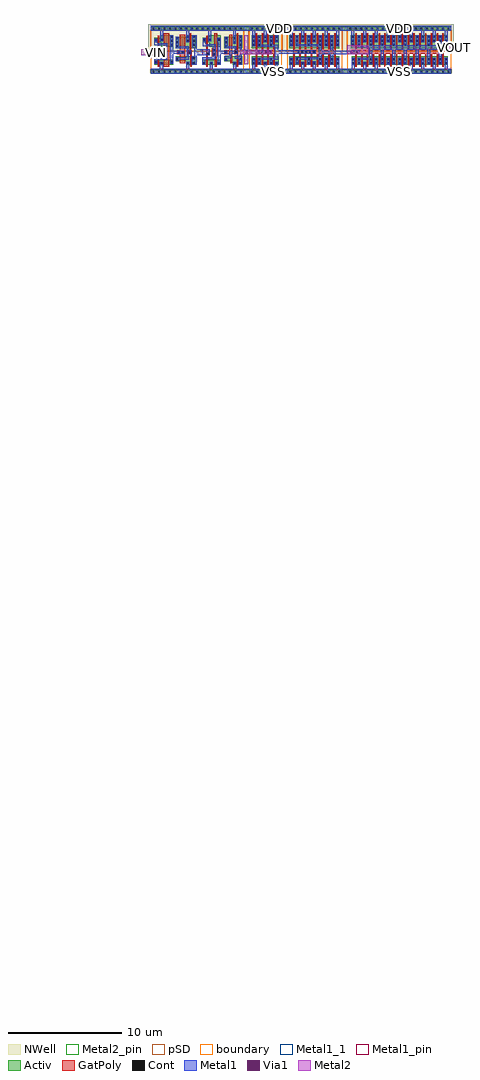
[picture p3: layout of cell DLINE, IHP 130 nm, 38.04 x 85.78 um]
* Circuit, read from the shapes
.subckt DLINE VDD VIN VOUT VSS
XM1 VSS VIN n1 VSS sg13_lv_nmos w=0.42u l=0.13u
XM2 n2 n1 VSS VSS sg13_lv_nmos w=0.42u l=0.5u
XM3 VSS n2 n3 VSS sg13_lv_nmos w=0.42u l=0.5u
XM4 sg13g2_dlygate4sd2_1_0/A n3 VSS VSS sg13_lv_nmos w=0.74u l=0.13u
XM5 VSS sg13g2_dlygate4sd2_1_0/A n4 VSS sg13_lv_nmos w=0.42u l=0.13u
XM6 n5 n4 VSS VSS sg13_lv_nmos w=0.42u l=0.18u
XM7 VSS n5 n6 VSS sg13_lv_nmos w=0.42u l=0.18u
XM8 sg13g2_dlygate4sd2_1_0/X n6 VSS VSS sg13_lv_nmos w=0.74u l=0.13u
XM9 n7 sg13g2_dlygate4sd2_1_0/X VSS VSS sg13_lv_nmos w=0.74u l=0.13u m=4
XM10 sg13g2_inv_16$1_4/A n7 VSS VSS sg13_lv_nmos w=0.74u l=0.13u m=8
XM11 VOUT sg13g2_inv_16$1_4/A VSS VSS sg13_lv_nmos w=0.74u l=0.13u m=16
XM12 VDD VIN n1 VDD sg13_lv_pmos w=0.42u l=0.13u
XM13 n2 n1 VDD VDD sg13_lv_pmos w=1u l=0.5u
XM14 VDD n2 n3 VDD sg13_lv_pmos w=1u l=0.5u
XM15 sg13g2_dlygate4sd2_1_0/A n3 VDD VDD sg13_lv_pmos w=1.12u l=0.13u
XM16 VDD sg13g2_dlygate4sd2_1_0/A n4 VDD sg13_lv_pmos w=0.42u l=0.13u
XM17 n5 n4 VDD VDD sg13_lv_pmos w=1u l=0.25u
XM18 VDD n5 n6 VDD sg13_lv_pmos w=1u l=0.25u
XM19 sg13g2_dlygate4sd2_1_0/X n6 VDD VDD sg13_lv_pmos w=1.12u l=0.13u
XM20 n7 sg13g2_dlygate4sd2_1_0/X VDD VDD sg13_lv_pmos w=1.12u l=0.13u m=4
XM21 sg13g2_inv_16$1_4/A n7 VDD VDD sg13_lv_pmos w=1.12u l=0.13u m=8
XM22 VOUT sg13g2_inv_16$1_4/A VDD VDD sg13_lv_pmos w=1.12u l=0.13u m=16
.ends

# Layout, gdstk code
from math import pi, radians
import gdstk
lib = gdstk.Library(unit=1e-6, precision=1e-09)
def R(c, l, rs):  # rectangles x0, y0, x1, y1
    for r in rs: c.add(gdstk.rectangle(r[:2], r[2:], *l))
def A(c, l, x, y, w, h, nx, ny, dx, dy):  # array of equal rectangles
    R(c, l, [(x+i*dx, y+j*dy, x+i*dx+w, y+j*dy+h) for i in range(nx) for j in range(ny)])
def P(c, l, *ps):  # polygons
    for p in ps: c.add(gdstk.Polygon(p, *l))
Activ = (1, 0)
GatPoly = (5, 0)
Cont = (6, 0)
Metal1 = (8, 0)
Metal1_1 = (8, 1)
Metal1_pin = (8, 2)
Metal2 = (10, 0)
Metal2_pin = (10, 2)
pSD = (14, 0)
Via1 = (19, 0)
NWell = (31, 0)
boundary = (189, 4)

sg13g2_dlygate4sd2_1 = lib.new_cell('sg13g2_dlygate4sd2_1')
R(sg13g2_dlygate4sd2_1, Activ, [(-4.79,81.345,-0.95,81.645), (-4.6,82.085,-2.98,82.505), (-4.79,85.125,-0.95,85.425)])
P(sg13g2_dlygate4sd2_1, Activ, [(-1.895,82.085),(-1.895,82.405),(-2.66,82.405),(-2.66,82.825),(-1.085,82.825),(-1.085,82.085)],
  [(-2.66,83.555),(-2.66,84.555),(-1.88,84.555),(-1.88,84.675),(-1.085,84.675),(-1.085,83.555)],
  [(-3.99,83.675),(-3.99,84.05),(-4.57,84.05),(-4.57,84.47),(-3.99,84.47),(-3.99,84.675),(-2.95,84.675),(-2.95,83.675)])
P(sg13g2_dlygate4sd2_1, GatPoly, [(-2.145,82.225),(-2.145,83.015),(-2.67,83.015),(-2.67,83.345),(-2.215,83.345),(-2.215,84.735),(-1.965,84.735),(-1.965,82.225)],
  [(-4.26,81.905),(-4.26,83.975),(-4.23,83.975),(-4.23,84.65),(-4.1,84.65),(-4.1,83.235),(-3.95,83.235),(-3.95,82.905),(-4.13,82.905),(-4.13,81.905)],
  [(-3.5,81.905),(-3.5,82.845),(-3.74,82.845),(-3.74,83.515),(-3.54,83.515),(-3.54,84.855),(-3.29,84.855),(-3.29,82.845),(-3.32,82.845),(-3.32,81.905)],
  [(-1.555,81.905),(-1.555,83.01),(-1.77,83.01),(-1.77,83.34),(-1.555,83.34),(-1.555,84.855),(-1.425,84.855),(-1.425,81.905)])
A(sg13g2_dlygate4sd2_1, Cont, -4.63, 81.415, 0.16, 0.16, 8, 2, 0.48, 3.78)
A(sg13g2_dlygate4sd2_1, Cont, -2.575, 83.645, 0.16, 0.16, 1, 3, 0, 0.34)
A(sg13g2_dlygate4sd2_1, Cont, -1.315, 83.765, 0.16, 0.16, 1, 3, 0, 0.34)
R(sg13g2_dlygate4sd2_1, Cont, [(-4.53,82.155,-4.37,82.315), (-3.88,82.155,-3.72,82.315), (-3.21,82.155,-3.05,82.315), (-1.825,82.155,-1.665,82.315), (-1.315,82.155,-1.155,82.315), (-1.315,82.495,-1.155,82.655), (-2.59,82.51,-2.43,82.67), (-3.625,82.93,-3.465,83.09), (-4.185,82.99,-4.025,83.15), (-1.685,83.095,-1.525,83.255), (-2.6,83.1,-2.44,83.26), (-3.625,83.27,-3.465,83.43), (-1.84,83.99,-1.68,84.15), (-4.5,84.195,-4.34,84.355), (-3.99,84.195,-3.83,84.355), (-3.18,84.195,-3.02,84.355), (-1.84,84.33,-1.68,84.49)])
R(sg13g2_dlygate4sd2_1, Metal1, [(-4.585,82.92,-3.955,83.44)])
P(sg13g2_dlygate4sd2_1, Metal1, [(-2.635,82.455),(-2.635,82.855),(-2.21,82.855),(-2.21,83.305),(-1.745,83.305),(-1.745,83.525),(-2.625,83.525),(-2.625,84.535),(-2.365,84.535),(-2.365,83.7),(-1.585,83.7),(-1.585,83.305),(-1.475,83.305),(-1.475,83.045),(-2.05,83.045),(-2.05,82.655),(-2.395,82.655),(-2.395,82.455)],
  [(-3.27,82.105),(-3.27,82.365),(-3.21,82.365),(-3.21,84.11),(-3.27,84.11),(-3.27,84.44),(-2.965,84.44),(-2.965,83.31),(-2.39,83.31),(-2.39,83.05),(-2.98,83.05),(-2.98,82.105)],
  [(-4.58,82.105),(-4.58,82.735),(-3.67,82.735),(-3.67,83.69),(-4.55,83.69),(-4.55,84.405),(-4.29,84.405),(-4.29,83.895),(-3.415,83.895),(-3.415,82.56),(-4.31,82.56),(-4.31,82.105)],
  [(-1.365,82.105),(-1.365,82.61),(-1.725,82.61),(-1.725,82.865),(-1.295,82.865),(-1.295,83.715),(-1.36,83.715),(-1.36,84.655),(-1.105,84.655),(-1.105,82.105)],
  [(-1.89,83.95),(-1.89,85.055),(-3.78,85.055),(-3.78,84.145),(-4.045,84.145),(-4.045,85.055),(-4.79,85.055),(-4.79,85.495),(-0.95,85.495),(-0.95,85.055),(-1.63,85.055),(-1.63,83.95)],
  [(-4.79,81.275),(-4.79,81.715),(-3.93,81.715),(-3.93,82.365),(-3.67,82.365),(-3.67,81.715),(-1.875,81.715),(-1.875,82.365),(-1.615,82.365),(-1.615,81.715),(-0.95,81.715),(-0.95,81.275)])
R(sg13g2_dlygate4sd2_1, Metal1_pin, [(-4.79,81.275,-0.95,81.715), (-1.725,82.61,-1.105,82.865), (-4.585,82.92,-3.955,83.44), (-4.79,85.055,-0.95,85.495)])
R(sg13g2_dlygate4sd2_1, pSD, [(-4.86,81.315,-0.88,81.675), (-4.86,83.255,-0.88,85.095)])
R(sg13g2_dlygate4sd2_1, NWell, [(-5.03,83.245,-0.71,85.665)])
R(sg13g2_dlygate4sd2_1, boundary, [(-4.79,81.495,-0.95,85.275)])
sg13g2_dlygate4sd2_1.add(gdstk.Label('X', (-1.43,82.755), layer=8, texttype=25))
sg13g2_dlygate4sd2_1.add(gdstk.Label('VDD', (-2.705,85.285), layer=8, texttype=25))
sg13g2_dlygate4sd2_1.add(gdstk.Label('VSS', (-2.59,81.5), layer=8, texttype=25))
sg13g2_dlygate4sd2_1.add(gdstk.Label('A', (-4.27,83.175), layer=8, texttype=25))

sg13g2_inv_4 = lib.new_cell('sg13g2_inv_4')
R(sg13g2_inv_4, Activ, [(-4.79,81.345,-1.91,81.645), (-4.545,82.085,-2.205,82.825), (-4.545,83.555,-2.205,84.675), (-4.79,85.125,-1.91,85.425)])
P(sg13g2_inv_4, GatPoly, [(-4.205,81.905),(-4.205,84.855),(-4.075,84.855),(-4.075,83.395),(-3.695,83.395),(-3.695,84.855),(-3.565,84.855),(-3.565,83.395),(-3.185,83.395),(-3.185,84.855),(-3.055,84.855),(-3.055,83.395),(-2.675,83.395),(-2.675,84.855),(-2.545,84.855),(-2.545,81.905),(-2.675,81.905),(-2.675,83.065),(-3.055,83.065),(-3.055,81.905),(-3.185,81.905),(-3.185,83.065),(-3.565,83.065),(-3.565,81.905),(-3.695,81.905),(-3.695,83.065),(-4.075,83.065),(-4.075,81.905)])
A(sg13g2_inv_4, Cont, -4.475, 82.155, 0.16, 0.16, 5, 2, 0.51, 2.285)
A(sg13g2_inv_4, Cont, -4.055, 83.15, 0.16, 0.16, 4, 1, 0.34, 0)
R(sg13g2_inv_4, Cont, [(-4.63,81.415,-4.47,81.575), (-4.63,81.415,-4.47,81.575), (-4.15,81.415,-3.99,81.575), (-4.15,81.415,-3.99,81.575), (-3.67,81.415,-3.51,81.575), (-3.67,81.415,-3.51,81.575), (-3.19,81.415,-3.03,81.575), (-3.19,81.415,-3.03,81.575), (-2.71,81.415,-2.55,81.575), (-2.71,81.415,-2.55,81.575), (-2.23,81.415,-2.07,81.575), (-2.23,81.415,-2.07,81.575), (-4.475,82.495,-4.315,82.655), (-3.965,82.495,-3.805,82.655), (-2.945,82.495,-2.785,82.655), (-4.475,83.75,-4.315,83.91), (-3.965,83.75,-3.805,83.91), (-2.945,83.75,-2.785,83.91), (-3.455,84.09,-3.295,84.25), (-2.435,84.09,-2.275,84.25), (-4.475,84.1,-4.315,84.26), (-3.965,84.1,-3.805,84.26), (-2.945,84.1,-2.785,84.26), (-4.63,85.195,-4.47,85.355), (-4.63,85.195,-4.47,85.355), (-4.15,85.195,-3.99,85.355), (-4.15,85.195,-3.99,85.355), (-3.67,85.195,-3.51,85.355), (-3.67,85.195,-3.51,85.355), (-3.19,85.195,-3.03,85.355), (-3.19,85.195,-3.03,85.355), (-2.71,85.195,-2.55,85.355), (-2.71,85.195,-2.55,85.355), (-2.23,85.195,-2.07,85.355), (-2.23,85.195,-2.07,85.355)])
R(sg13g2_inv_4, Metal1, [(-4.31,83.015,-2.79,83.395)])
P(sg13g2_inv_4, Metal1, [(-4.015,82.105),(-4.015,82.705),(-2.545,82.705),(-2.545,83.665),(-4.015,83.665),(-4.015,84.65),(-3.755,84.65),(-3.755,83.835),(-2.995,83.835),(-2.995,84.65),(-2.735,84.65),(-2.735,83.835),(-2.25,83.835),(-2.25,82.545),(-2.735,82.545),(-2.735,82.105),(-2.995,82.105),(-2.995,82.545),(-3.755,82.545),(-3.755,82.105)],
  [(-4.525,83.7),(-4.525,85.055),(-4.79,85.055),(-4.79,85.495),(-1.91,85.495),(-1.91,85.055),(-2.225,85.055),(-2.225,84.04),(-2.485,84.04),(-2.485,85.055),(-3.245,85.055),(-3.245,84.04),(-3.505,84.04),(-3.505,85.055),(-4.265,85.055),(-4.265,83.7)],
  [(-4.79,81.275),(-4.79,81.715),(-4.525,81.715),(-4.525,82.705),(-4.265,82.705),(-4.265,81.715),(-3.51,81.715),(-3.51,82.365),(-3.24,82.365),(-3.24,81.715),(-2.485,81.715),(-2.485,82.365),(-2.225,82.365),(-2.225,81.715),(-1.91,81.715),(-1.91,81.275)])
R(sg13g2_inv_4, Metal1_pin, [(-4.79,81.275,-1.91,81.715), (-4.79,85.055,-1.91,85.495)])
R(sg13g2_inv_4, pSD, [(-4.86,81.315,-1.84,81.675), (-4.86,83.255,-1.84,85.095)])
R(sg13g2_inv_4, NWell, [(-5.03,83.245,-1.67,85.665)])
R(sg13g2_inv_4, boundary, [(-4.79,81.495,-1.91,85.275)])
sg13g2_inv_4.add(gdstk.Label('VDD', (-2.865,85.295), layer=8, texttype=25))
sg13g2_inv_4.add(gdstk.Label('VSS', (-3.385,81.5), layer=8, texttype=25))

sg13g2_inv_8 = lib.new_cell('sg13g2_inv_8')
R(sg13g2_inv_8, Activ, [(-4.79,81.345,0.01,81.645), (-4.605,82.085,-0.215,82.825), (-4.605,83.555,-0.215,84.675), (-4.79,85.125,0.01,85.425)])
P(sg13g2_inv_8, GatPoly, [(-4.265,81.905),(-4.265,84.855),(-4.135,84.855),(-4.135,83.395),(-3.755,83.395),(-3.755,84.855),(-3.625,84.855),(-3.625,83.395),(-3.245,83.395),(-3.245,84.855),(-3.115,84.855),(-3.115,83.395),(-2.735,83.395),(-2.735,84.855),(-2.605,84.855),(-2.605,83.395),(-2.225,83.395),(-2.225,84.855),(-2.095,84.855),(-2.095,83.395),(-1.715,83.395),(-1.715,84.855),(-1.585,84.855),(-1.585,83.395),(-1.205,83.395),(-1.205,84.855),(-1.075,84.855),(-1.075,83.395),(-0.685,83.395),(-0.685,84.855),(-0.555,84.855),(-0.555,81.905),(-0.685,81.905),(-0.685,83.065),(-1.075,83.065),(-1.075,81.905),(-1.205,81.905),(-1.205,83.065),(-1.585,83.065),(-1.585,81.905),(-1.715,81.905),(-1.715,83.065),(-2.095,83.065),(-2.095,81.905),(-2.225,81.905),(-2.225,83.065),(-2.605,83.065),(-2.605,81.905),(-2.735,81.905),(-2.735,83.065),(-3.115,83.065),(-3.115,81.905),(-3.245,81.905),(-3.245,83.065),(-3.625,83.065),(-3.625,81.905),(-3.755,81.905),(-3.755,83.065),(-4.135,83.065),(-4.135,81.905)])
A(sg13g2_inv_8, Cont, -4.535, 82.155, 0.16, 0.16, 8, 2, 0.51, 1.95)
A(sg13g2_inv_8, Cont, -4.025, 82.495, 0.16, 0.16, 3, 2, 1.02, 1.27)
A(sg13g2_inv_8, Cont, -3.9, 83.15, 0.16, 0.16, 5, 1, 0.34, 0)
A(sg13g2_inv_8, Cont, -0.445, 83.765, 0.16, 0.16, 1, 3, 0, 0.34)
A(sg13g2_inv_8, Cont, -4.535, 84.445, 0.16, 0.16, 8, 1, 0.51, 0)
R(sg13g2_inv_8, Cont, [(-4.63,81.415,-4.47,81.575), (-4.63,81.415,-4.47,81.575), (-4.15,81.415,-3.99,81.575), (-4.15,81.415,-3.99,81.575), (-3.67,81.415,-3.51,81.575), (-3.67,81.415,-3.51,81.575), (-3.19,81.415,-3.03,81.575), (-3.19,81.415,-3.03,81.575), (-2.71,81.415,-2.55,81.575), (-2.71,81.415,-2.55,81.575), (-2.23,81.415,-2.07,81.575), (-2.23,81.415,-2.07,81.575), (-1.75,81.415,-1.59,81.575), (-1.75,81.415,-1.59,81.575), (-1.27,81.415,-1.11,81.575), (-1.27,81.415,-1.11,81.575), (-0.79,81.415,-0.63,81.575), (-0.79,81.415,-0.63,81.575), (-0.31,81.415,-0.15,81.575), (-0.31,81.415,-0.15,81.575), (-0.445,82.155,-0.285,82.315), (-4.535,82.495,-4.375,82.655), (-1.475,82.495,-1.315,82.655), (-0.965,82.495,-0.805,82.655), (-0.445,82.495,-0.285,82.655), (-4.535,83.765,-4.375,83.925), (-1.475,83.765,-1.315,83.925), (-0.965,83.765,-0.805,83.925), (-4.63,85.195,-4.47,85.355), (-4.63,85.195,-4.47,85.355), (-4.15,85.195,-3.99,85.355), (-4.15,85.195,-3.99,85.355), (-3.67,85.195,-3.51,85.355), (-3.67,85.195,-3.51,85.355), (-3.19,85.195,-3.03,85.355), (-3.19,85.195,-3.03,85.355), (-2.71,85.195,-2.55,85.355), (-2.71,85.195,-2.55,85.355), (-2.23,85.195,-2.07,85.355), (-2.23,85.195,-2.07,85.355), (-1.75,85.195,-1.59,85.355), (-1.75,85.195,-1.59,85.355), (-1.27,85.195,-1.11,85.355), (-1.27,85.195,-1.11,85.355), (-0.79,85.195,-0.63,85.355), (-0.79,85.195,-0.63,85.355), (-0.31,85.195,-0.15,85.355), (-0.31,85.195,-0.15,85.355)])
R(sg13g2_inv_8, Metal1, [(-3.985,83.03,-2.295,83.36)])
P(sg13g2_inv_8, Metal1, [(-4.79,81.275),(-4.79,81.715),(-4.585,81.715),(-4.585,82.705),(-4.325,82.705),(-4.325,81.715),(-3.565,81.715),(-3.565,82.365),(-3.305,82.365),(-3.305,81.715),(-2.545,81.715),(-2.545,82.385),(-2.285,82.385),(-2.285,81.715),(-1.525,81.715),(-1.525,82.705),(-1.265,82.705),(-1.265,81.715),(-0.495,81.715),(-0.495,82.705),(-0.235,82.705),(-0.235,81.715),(0.01,81.715),(0.01,81.275)],
  [(-4.585,83.715),(-4.585,85.055),(-4.79,85.055),(-4.79,85.495),(0.01,85.495),(0.01,85.055),(-0.235,85.055),(-0.235,83.715),(-0.495,83.715),(-0.495,85.055),(-1.265,85.055),(-1.265,83.715),(-1.525,83.715),(-1.525,85.055),(-2.285,85.055),(-2.285,84.055),(-2.545,84.055),(-2.545,85.055),(-3.305,85.055),(-3.305,84.055),(-3.565,84.055),(-3.565,85.055),(-4.325,85.055),(-4.325,83.715)],
  [(-3.055,82.105),(-3.055,82.545),(-3.81,82.545),(-3.81,82.115),(-4.075,82.115),(-4.075,82.725),(-2.05,82.725),(-2.05,83.715),(-4.075,83.715),(-4.075,84.655),(-3.815,84.655),(-3.815,83.875),(-3.055,83.875),(-3.055,84.655),(-2.795,84.655),(-2.795,83.875),(-2.035,83.875),(-2.035,84.655),(-1.775,84.655),(-1.775,83.335),(-1.015,83.335),(-1.015,84.655),(-0.755,84.655),(-0.755,82.105),(-1.015,82.105),(-1.015,83.025),(-1.775,83.025),(-1.775,82.105),(-2.035,82.105),(-2.035,82.565),(-2.79,82.565),(-2.79,82.105)])
R(sg13g2_inv_8, Metal1_pin, [(-4.79,81.275,0.01,81.715), (-4.79,85.055,0.01,85.495)])
R(sg13g2_inv_8, pSD, [(-4.86,81.315,0.08,81.675), (-4.86,83.255,0.08,85.095)])
R(sg13g2_inv_8, NWell, [(-5.03,83.245,0.25,85.665)])
R(sg13g2_inv_8, boundary, [(-4.79,81.495,0.01,85.275)])
sg13g2_inv_8.add(gdstk.Label('VSS', (-2.48,81.475), layer=8, texttype=25))
sg13g2_inv_8.add(gdstk.Label('VDD', (-2.08,85.275), layer=8, texttype=25))

sg13g2_dlygate4sd3_1 = lib.new_cell('sg13g2_dlygate4sd3_1')
R(sg13g2_dlygate4sd3_1, Activ, [(-4.79,81.345,-0.47,81.645), (-4.51,82.085,-2.82,82.505), (-4.79,85.125,-0.47,85.425)])
P(sg13g2_dlygate4sd3_1, Activ, [(-2.6,83.555),(-2.6,84.555),(-1.69,84.555),(-1.69,84.675),(-0.84,84.675),(-0.84,83.555)],
  [(-1.68,82.085),(-1.68,82.405),(-2.6,82.405),(-2.6,82.825),(-0.87,82.825),(-0.87,82.085)],
  [(-3.91,83.675),(-3.91,84.05),(-4.51,84.05),(-4.51,84.47),(-3.91,84.47),(-3.91,84.675),(-2.82,84.675),(-2.82,83.675)])
R(sg13g2_dlygate4sd3_1, GatPoly, [(-3.66,81.905,-3.16,84.855)])
P(sg13g2_dlygate4sd3_1, GatPoly, [(-4.17,81.905),(-4.17,82.905),(-4.2,82.905),(-4.2,83.235),(-4.17,83.235),(-4.17,84.65),(-4.04,84.65),(-4.04,83.235),(-3.87,83.235),(-3.87,82.905),(-4.04,82.905),(-4.04,81.905)],
  [(-1.34,81.905),(-1.34,83.01),(-1.545,83.01),(-1.545,83.34),(-1.35,83.34),(-1.35,84.855),(-1.22,84.855),(-1.22,83.34),(-1.18,83.34),(-1.18,83.01),(-1.21,83.01),(-1.21,81.905)],
  [(-2.26,82.225),(-2.26,83.015),(-2.475,83.015),(-2.475,83.345),(-2.26,83.345),(-2.26,84.735),(-1.76,84.735),(-1.76,83.345),(-1.755,83.345),(-1.755,83.015),(-1.76,83.015),(-1.76,82.225)])
A(sg13g2_dlygate4sd3_1, Cont, -2.53, 83.645, 0.16, 0.16, 1, 3, 0, 0.34)
A(sg13g2_dlygate4sd3_1, Cont, -3.05, 83.765, 0.16, 0.16, 1, 3, 0, 0.34)
A(sg13g2_dlygate4sd3_1, Cont, -1.07, 83.765, 0.16, 0.16, 1, 3, 0, 0.34)
R(sg13g2_dlygate4sd3_1, Cont, [(-4.63,81.415,-4.47,81.575), (-4.63,81.415,-4.47,81.575), (-4.15,81.415,-3.99,81.575), (-4.15,81.415,-3.99,81.575), (-3.67,81.415,-3.51,81.575), (-3.67,81.415,-3.51,81.575), (-3.19,81.415,-3.03,81.575), (-3.19,81.415,-3.03,81.575), (-2.71,81.415,-2.55,81.575), (-2.71,81.415,-2.55,81.575), (-2.23,81.415,-2.07,81.575), (-2.23,81.415,-2.07,81.575), (-1.75,81.415,-1.59,81.575), (-1.75,81.415,-1.59,81.575), (-1.27,81.415,-1.11,81.575), (-1.27,81.415,-1.11,81.575), (-0.79,81.415,-0.63,81.575), (-0.79,81.415,-0.63,81.575), (-3.93,82.155,-3.77,82.315), (-1.1,82.155,-0.94,82.315), (-1.61,82.16,-1.45,82.32), (-4.44,82.21,-4.28,82.37), (-3.05,82.21,-2.89,82.37), (-2.53,82.505,-2.37,82.665), (-1.1,82.585,-0.94,82.745), (-3.55,82.925,-3.39,83.085), (-4.12,82.985,-3.96,83.145), (-1.465,83.09,-1.305,83.25), (-2.395,83.095,-2.235,83.255), (-2.055,83.095,-1.895,83.255), (-3.55,83.28,-3.39,83.44), (-1.62,84.105,-1.46,84.265), (-4.44,84.19,-4.28,84.35), (-3.93,84.19,-3.77,84.35), (-1.62,84.445,-1.46,84.605), (-4.63,85.195,-4.47,85.355), (-4.63,85.195,-4.47,85.355), (-4.15,85.195,-3.99,85.355), (-4.15,85.195,-3.99,85.355), (-3.67,85.195,-3.51,85.355), (-3.67,85.195,-3.51,85.355), (-3.19,85.195,-3.03,85.355), (-3.19,85.195,-3.03,85.355), (-2.71,85.195,-2.55,85.355), (-2.71,85.195,-2.55,85.355), (-2.23,85.195,-2.07,85.355), (-2.23,85.195,-2.07,85.355), (-1.75,85.195,-1.59,85.355), (-1.75,85.195,-1.59,85.355), (-1.27,85.195,-1.11,85.355), (-1.27,85.195,-1.11,85.355), (-0.79,85.195,-0.63,85.355), (-0.79,85.195,-0.63,85.355)])
R(sg13g2_dlygate4sd3_1, Metal1, [(-4.505,82.905,-3.875,83.575)])
P(sg13g2_dlygate4sd3_1, Metal1, [(-1.18,82.09),(-1.18,82.835),(-0.985,82.835),(-0.985,83.57),(-1.135,83.57),(-1.135,84.665),(-0.77,84.665),(-0.77,82.09)],
  [(-4.79,81.275),(-4.79,81.715),(-3.99,81.715),(-3.99,82.33),(-3.72,82.33),(-3.72,81.715),(-1.66,81.715),(-1.66,82.345),(-1.4,82.345),(-1.4,81.715),(-0.47,81.715),(-0.47,81.275)],
  [(-1.67,84.055),(-1.67,85.055),(-3.72,85.055),(-3.72,84.16),(-3.98,84.16),(-3.98,85.055),(-4.79,85.055),(-4.79,85.495),(-0.47,85.495),(-0.47,85.055),(-1.41,85.055),(-1.41,84.055)],
  [(-2.585,82.44),(-2.585,82.73),(-1.64,82.73),(-1.64,83.54),(-2.58,83.54),(-2.58,84.535),(-2.32,84.535),(-2.32,83.71),(-1.45,83.71),(-1.45,83.34),(-1.255,83.34),(-1.255,83.01),(-1.45,83.01),(-1.45,82.54),(-2.32,82.54),(-2.32,82.44)],
  [(-3.07,82.16),(-3.07,83.715),(-3.1,83.715),(-3.1,84.655),(-2.835,84.655),(-2.835,83.305),(-1.865,83.305),(-1.865,83.045),(-2.835,83.045),(-2.835,82.16)],
  [(-4.49,82.185),(-4.49,82.7),(-3.615,82.7),(-3.615,83.815),(-4.49,83.815),(-4.49,84.375),(-4.23,84.375),(-4.23,83.975),(-3.335,83.975),(-3.335,82.51),(-4.23,82.51),(-4.23,82.185)])
R(sg13g2_dlygate4sd3_1, Metal1_pin, [(-4.79,81.275,-0.47,81.715), (-4.505,82.905,-3.875,83.575), (-1.135,83.57,-0.77,84.665), (-4.79,85.055,-0.47,85.495)])
R(sg13g2_dlygate4sd3_1, pSD, [(-4.86,81.315,-0.4,81.675), (-4.86,83.255,-0.4,85.095)])
R(sg13g2_dlygate4sd3_1, NWell, [(-5.03,83.245,-0.23,85.665)])
R(sg13g2_dlygate4sd3_1, boundary, [(-4.79,81.495,-0.47,85.275)])
sg13g2_dlygate4sd3_1.add(gdstk.Label('A', (-4.17,83.25), layer=8, texttype=25))
sg13g2_dlygate4sd3_1.add(gdstk.Label('VDD', (-2.63,85.275), layer=8, texttype=25))
sg13g2_dlygate4sd3_1.add(gdstk.Label('VSS', (-2.63,81.495), layer=8, texttype=25))
sg13g2_dlygate4sd3_1.add(gdstk.Label('X', (-0.925,84.165), layer=8, texttype=25))

sg13g2_inv_16_1 = lib.new_cell('sg13g2_inv_16$1')
R(sg13g2_inv_16_1, Activ, [(4.79,81.345,13.91,81.645), (5.095,82.085,13.555,82.825), (5.095,83.555,13.605,84.675), (4.79,85.125,13.91,85.425)])
R(sg13g2_inv_16_1, GatPoly, [(13.215,83.065,13.575,83.395)])
P(sg13g2_inv_16_1, GatPoly, [(5.435,81.905),(5.435,84.855),(5.565,84.855),(5.565,83.395),(5.945,83.395),(5.945,84.855),(6.075,84.855),(6.075,83.395),(6.455,83.395),(6.455,84.855),(6.585,84.855),(6.585,83.395),(6.965,83.395),(6.965,84.855),(7.095,84.855),(7.095,83.395),(7.475,83.395),(7.475,84.855),(7.605,84.855),(7.605,83.395),(7.985,83.395),(7.985,84.855),(8.115,84.855),(8.115,83.395),(8.495,83.395),(8.495,84.855),(8.625,84.855),(8.625,83.395),(9.005,83.395),(9.005,84.855),(9.135,84.855),(9.135,83.395),(9.515,83.395),(9.515,84.855),(9.645,84.855),(9.645,83.395),(10.025,83.395),(10.025,84.855),(10.155,84.855),(10.155,83.395),(10.535,83.395),(10.535,84.855),(10.665,84.855),(10.665,83.395),(11.045,83.395),(11.045,84.855),(11.175,84.855),(11.175,83.395),(11.555,83.395),(11.555,84.855),(11.685,84.855),(11.685,83.395),(12.065,83.395),(12.065,84.855),(12.195,84.855),(12.195,83.395),(12.575,83.395),(12.575,84.855),(12.705,84.855),(12.705,83.395),(13.085,83.395),(13.085,84.855),(13.215,84.855),(13.215,81.905),(13.085,81.905),(13.085,83.065),(12.705,83.065),(12.705,81.905),(12.575,81.905),(12.575,83.065),(12.195,83.065),(12.195,81.905),(12.065,81.905),(12.065,83.065),(11.685,83.065),(11.685,81.905),(11.555,81.905),(11.555,83.065),(11.175,83.065),(11.175,81.905),(11.045,81.905),(11.045,83.065),(10.665,83.065),(10.665,81.905),(10.535,81.905),(10.535,83.065),(10.155,83.065),(10.155,81.905),(10.025,81.905),(10.025,83.065),(9.645,83.065),(9.645,81.905),(9.515,81.905),(9.515,83.065),(9.135,83.065),(9.135,81.905),(9.005,81.905),(9.005,83.065),(8.625,83.065),(8.625,81.905),(8.495,81.905),(8.495,83.065),(8.115,83.065),(8.115,81.905),(7.985,81.905),(7.985,83.065),(7.605,83.065),(7.605,81.905),(7.475,81.905),(7.475,83.065),(7.095,83.065),(7.095,81.905),(6.965,81.905),(6.965,83.065),(6.585,83.065),(6.585,81.905),(6.455,81.905),(6.455,83.065),(6.075,83.065),(6.075,81.905),(5.945,81.905),(5.945,83.065),(5.565,83.065),(5.565,81.905)])
A(sg13g2_inv_16_1, Cont, 5.165, 82.155, 0.16, 0.16, 17, 1, 0.51, 0)
A(sg13g2_inv_16_1, Cont, 5.165, 82.495, 0.16, 0.16, 14, 1, 0.51, 0)
A(sg13g2_inv_16_1, Cont, 5.675, 83.765, 0.16, 0.16, 8, 1, 1.02, 0)
A(sg13g2_inv_16_1, Cont, 13.375, 83.765, 0.16, 0.16, 1, 3, 0, 0.34)
A(sg13g2_inv_16_1, Cont, 5.165, 84.105, 0.16, 0.16, 16, 2, 0.51, 0.34)
R(sg13g2_inv_16_1, Cont, [(4.95,81.415,5.11,81.575), (4.95,81.415,5.11,81.575), (5.43,81.415,5.59,81.575), (5.43,81.415,5.59,81.575), (5.91,81.415,6.07,81.575), (5.91,81.415,6.07,81.575), (6.39,81.415,6.55,81.575), (6.39,81.415,6.55,81.575), (6.87,81.415,7.03,81.575), (6.87,81.415,7.03,81.575), (7.35,81.415,7.51,81.575), (7.35,81.415,7.51,81.575), (7.83,81.415,7.99,81.575), (7.83,81.415,7.99,81.575), (8.31,81.415,8.47,81.575), (8.31,81.415,8.47,81.575), (8.79,81.415,8.95,81.575), (8.79,81.415,8.95,81.575), (9.27,81.415,9.43,81.575), (9.27,81.415,9.43,81.575), (9.75,81.415,9.91,81.575), (9.75,81.415,9.91,81.575), (10.23,81.415,10.39,81.575), (10.23,81.415,10.39,81.575), (10.71,81.415,10.87,81.575), (10.71,81.415,10.87,81.575), (11.19,81.415,11.35,81.575), (11.19,81.415,11.35,81.575), (11.67,81.415,11.83,81.575), (11.67,81.415,11.83,81.575), (12.15,81.415,12.31,81.575), (12.15,81.415,12.31,81.575), (12.63,81.415,12.79,81.575), (12.63,81.415,12.79,81.575), (13.11,81.415,13.27,81.575), (13.11,81.415,13.27,81.575), (13.59,81.415,13.75,81.575), (13.59,81.415,13.75,81.575), (12.815,82.495,12.975,82.655), (13.325,82.495,13.485,82.655), (12.985,83.145,13.145,83.305), (13.325,83.145,13.485,83.305), (5.165,83.765,5.325,83.925), (4.95,85.195,5.11,85.355), (4.95,85.195,5.11,85.355), (5.43,85.195,5.59,85.355), (5.43,85.195,5.59,85.355), (5.91,85.195,6.07,85.355), (5.91,85.195,6.07,85.355), (6.39,85.195,6.55,85.355), (6.39,85.195,6.55,85.355), (6.87,85.195,7.03,85.355), (6.87,85.195,7.03,85.355), (7.35,85.195,7.51,85.355), (7.35,85.195,7.51,85.355), (7.83,85.195,7.99,85.355), (7.83,85.195,7.99,85.355), (8.31,85.195,8.47,85.355), (8.31,85.195,8.47,85.355), (8.79,85.195,8.95,85.355), (8.79,85.195,8.95,85.355), (9.27,85.195,9.43,85.355), (9.27,85.195,9.43,85.355), (9.75,85.195,9.91,85.355), (9.75,85.195,9.91,85.355), (10.23,85.195,10.39,85.355), (10.23,85.195,10.39,85.355), (10.71,85.195,10.87,85.355), (10.71,85.195,10.87,85.355), (11.19,85.195,11.35,85.355), (11.19,85.195,11.35,85.355), (11.67,85.195,11.83,85.355), (11.67,85.195,11.83,85.355), (12.15,85.195,12.31,85.355), (12.15,85.195,12.31,85.355), (12.63,85.195,12.79,85.355), (12.63,85.195,12.79,85.355), (13.11,85.195,13.27,85.355), (13.11,85.195,13.27,85.355), (13.59,85.195,13.75,85.355), (13.59,85.195,13.75,85.355)])
R(sg13g2_inv_16_1, Metal1, [(12.815,82.985,13.575,83.365)])
P(sg13g2_inv_16_1, Metal1, [(4.79,81.275),(4.79,81.715),(5.115,81.715),(5.115,82.705),(5.375,82.705),(5.375,81.715),(6.135,81.715),(6.135,82.705),(6.395,82.705),(6.395,81.715),(7.155,81.715),(7.155,82.705),(7.415,82.705),(7.415,81.715),(8.175,81.715),(8.175,82.705),(8.435,82.705),(8.435,81.715),(9.195,81.715),(9.195,82.705),(9.455,82.705),(9.455,81.715),(10.215,81.715),(10.215,82.705),(10.475,82.705),(10.475,81.715),(11.235,81.715),(11.235,82.705),(11.495,82.705),(11.495,81.715),(12.255,81.715),(12.255,82.365),(12.515,82.365),(12.515,81.715),(13.275,81.715),(13.275,82.705),(13.535,82.705),(13.535,81.715),(13.91,81.715),(13.91,81.275)],
  [(5.115,83.715),(5.115,85.055),(4.79,85.055),(4.79,85.495),(13.91,85.495),(13.91,85.055),(13.585,85.055),(13.585,83.715),(13.325,83.715),(13.325,85.05),(12.515,85.05),(12.515,84.055),(12.255,84.055),(12.255,85.055),(11.495,85.055),(11.495,84.055),(11.235,84.055),(11.235,85.055),(10.475,85.055),(10.475,84.055),(10.215,84.055),(10.215,85.055),(9.455,85.055),(9.455,84.055),(9.195,84.055),(9.195,85.055),(8.435,85.055),(8.435,84.055),(8.175,84.055),(8.175,85.055),(7.415,85.055),(7.415,84.055),(7.155,84.055),(7.155,85.055),(6.395,85.055),(6.395,84.055),(6.135,84.055),(6.135,85.055),(5.375,85.055),(5.375,83.715)],
  [(7.665,82.12),(7.665,83.395),(6.905,83.395),(6.905,82.125),(6.645,82.125),(6.645,83.395),(5.885,83.395),(5.885,82.125),(5.625,82.125),(5.625,84.655),(5.885,84.655),(5.885,83.815),(6.645,83.815),(6.645,84.655),(6.905,84.655),(6.905,83.815),(7.665,83.815),(7.665,84.655),(7.925,84.655),(7.925,83.815),(8.685,83.815),(8.685,84.655),(8.945,84.655),(8.945,83.815),(9.705,83.815),(9.705,84.655),(9.965,84.655),(9.965,83.815),(10.725,83.815),(10.725,84.655),(10.985,84.655),(10.985,83.815),(11.745,83.815),(11.745,84.655),(12.005,84.655),(12.005,83.815),(12.765,83.815),(12.765,84.655),(13.025,84.655),(13.025,83.64),(12.005,83.64),(12.005,82.705),(13.025,82.705),(13.025,82.12),(12.765,82.12),(12.765,82.545),(12.005,82.545),(12.005,82.12),(11.745,82.12),(11.745,83.395),(10.985,83.395),(10.985,82.12),(10.725,82.12),(10.725,83.395),(9.965,83.395),(9.965,82.12),(9.705,82.12),(9.705,83.395),(8.945,83.395),(8.945,82.12),(8.685,82.12),(8.685,83.395),(7.925,83.395),(7.925,82.12)])
R(sg13g2_inv_16_1, Metal1_pin, [(4.79,81.275,13.91,81.715), (12.815,82.985,13.535,83.365), (5.885,83.395,7.925,83.815), (4.79,85.055,13.91,85.495)])
R(sg13g2_inv_16_1, pSD, [(4.725,81.315,13.98,81.675), (4.725,83.255,13.98,85.095)])
R(sg13g2_inv_16_1, NWell, [(4.55,83.245,14.15,85.665)])
R(sg13g2_inv_16_1, boundary, [(4.79,81.495,13.91,85.275)])
sg13g2_inv_16_1.add(gdstk.Label('VSS', (8.65,81.47), layer=8, texttype=25))
sg13g2_inv_16_1.add(gdstk.Label('VDD', (9.07,85.29), layer=8, texttype=25))
sg13g2_inv_16_1.add(gdstk.Label('A', (12.95,83.175), layer=8, texttype=25))
sg13g2_inv_16_1.add(gdstk.Label('Y', (6.95,83.555), layer=8, texttype=25))

dline = lib.new_cell('DLINE')
R(dline, Activ, [(17.73,89.565,18.21,89.865), (22.05,89.565,22.53,89.865), (25.41,89.565,25.89,89.865), (30.69,89.565,31.17,89.865), (17.73,93.345,18.21,93.645), (22.05,93.345,22.53,93.645), (25.41,93.345,25.89,93.645), (30.69,93.345,31.17,93.645)])
R(dline, Metal1, [(17.73,89.495,18.21,89.935), (22.05,89.495,22.53,89.935), (25.41,89.495,25.89,89.935), (30.69,89.495,31.17,89.935), (17.695,91.14,18.415,91.66), (21.705,91.235,23.01,91.615), (28.63,91.245,32.265,91.555), (25.04,91.25,26.695,91.58), (17.73,93.275,18.21,93.715), (22.05,93.275,22.53,93.715), (25.41,93.275,25.89,93.715), (30.69,93.275,31.17,93.715)])
P(dline, Metal1_1, [(2.705,8.11),(2.705,8.11),(2.705,8.11),(2.705,8.11)])
R(dline, Metal1_pin, [(35.7,89.64,35.83,89.77), (24.625,89.65,24.755,89.78), (14.36,91.34,14.49,91.47), (25.11,93.43,25.24,93.56), (35.69,93.445,35.82,93.575)])
R(dline, Metal2, [(22.12,90.33,22.46,92.875), (13.065,91.14,14.81,91.66), (31.145,91.205,33.04,91.585), (21.705,91.235,24.53,91.615), (31.145,91.585,33.04,92.035), (39.095,91.635,40.745,92.015)])
R(dline, Metal2_pin, [(14.355,91.345,14.485,91.475), (40.525,91.755,40.655,91.885)])
R(dline, pSD, [(17.8,89.535,18.14,89.895), (22.12,89.535,22.46,89.895), (25.48,89.535,25.82,89.895), (30.76,89.535,31.105,89.895)])
R(dline, Via1, [(14.33,91.325,14.52,91.515), (22.22,91.325,22.41,91.515), (23.255,91.325,23.445,91.515), (24.06,91.325,24.25,91.515), (31.405,91.325,31.595,91.515), (39.195,91.78,39.385,91.97)])
dline.add(gdstk.Reference(sg13g2_dlygate4sd2_1, (23,8.22)))
dline.add(gdstk.Reference(sg13g2_inv_4, (27.32,8.22)))
dline.add(gdstk.Reference(sg13g2_inv_8, (30.68,8.22)))
dline.add(gdstk.Reference(sg13g2_dlygate4sd3_1, (18.68,8.22)))
dline.add(gdstk.Reference(sg13g2_inv_16_1, (45.08,8.22), rotation=pi, x_reflection=True))
dline.add(gdstk.Label('VDD', (25.175,93.495), layer=8, texttype=25))
dline.add(gdstk.Label('VSS', (24.69,89.715), layer=8, texttype=25))
dline.add(gdstk.Label('VIN', (14.425,91.405), layer=8, texttype=25))
dline.add(gdstk.Label('VSS', (35.765,89.705), layer=8, texttype=25))
dline.add(gdstk.Label('VDD', (35.755,93.51), layer=8, texttype=25))
dline.add(gdstk.Label('VOUT', (40.59,91.82), layer=10, texttype=25))
dline.add(gdstk.Label('VIN', (14.42,91.41), layer=10, texttype=25))

lib.write_gds('DLINE.gds')
